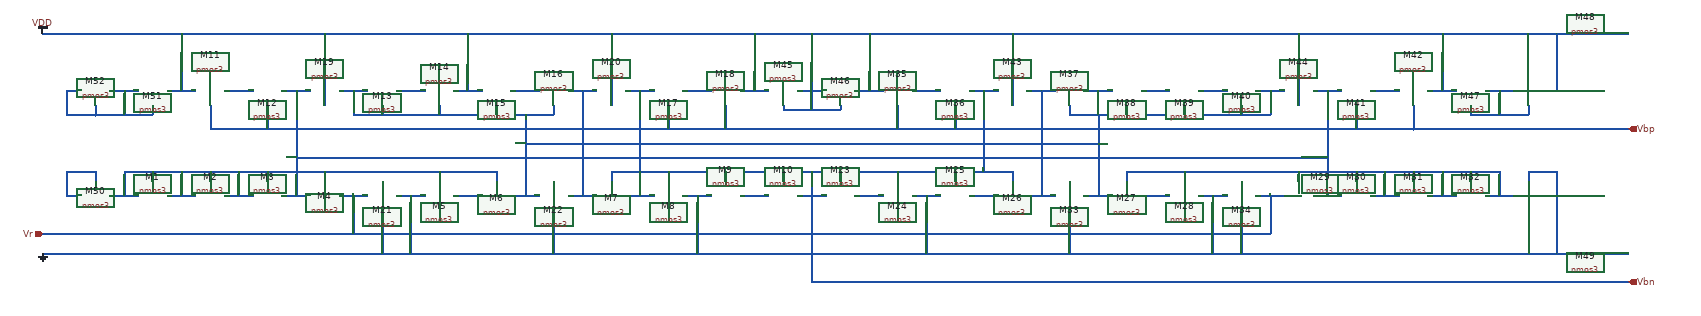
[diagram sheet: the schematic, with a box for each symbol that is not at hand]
v {xschem version=2.9.9 file_version=1.2 }
G {}
K {}
V {}
S {}
E {}
N 650 -270 650 -250 { lab=#net1}
N 530 -270 530 -250 { lab=#net1}
N 410 -270 410 -250 { lab=#net1}
N 290 -270 290 -250 { lab=#net1}
N 320 -220 380 -220 { lab=#net1}
N 350 -270 350 -220 { lab=#net1}
N 440 -220 500 -220 { lab=#net1}
N 470 -270 470 -220 { lab=#net1}
N 560 -220 620 -220 { lab=#net1}
N 590 -270 590 -220 { lab=#net1}
N 440 -440 500 -440 { lab=#net2}
N 800 -440 860 -440 { lab=#net3}
N 1040 -440 1100 -440 { lab=#net4}
N 1400 -440 1460 -440 { lab=#net5}
N 770 -410 770 -390 { lab=#net6}
N 1130 -410 1130 -390 { lab=#net6}
N 890 -410 890 -390 { lab=#net6}
N 1010 -410 1010 -390 { lab=#net6}
N 410 -410 410 -360 { lab=Vbp}
N 1490 -410 1490 -360 { lab=Vbp}
N 1370 -410 1370 -360 { lab=Vbp}
N 530 -410 530 -360 { lab=Vbp}
N 350 -560 350 -440 { lab=#net7}
N 1550 -560 1550 -440 { lab=#net7}
N 920 -440 980 -440 { lab=#net7}
N 950 -560 950 -440 { lab=#net7}
N 890 -270 890 -250 { lab=#net1}
N 1010 -270 1010 -250 { lab=#net1}
N 920 -220 980 -220 { lab=#net8}
N 1280 -220 1340 -220 { lab=#net9}
N 1520 -220 1580 -220 { lab=#net10}
N 710 -220 710 -140 { lab=Vr}
N 1250 -270 1250 -250 { lab=Vbn}
N 1610 -270 1610 -250 { lab=Vbn}
N 1490 -270 1490 -250 { lab=Vbn}
N 1370 -270 1370 -250 { lab=Vbn}
N 1400 -220 1460 -220 { lab=GND}
N 1430 -220 1430 -100 { lab=GND}
N 830 -220 830 -100 { lab=GND}
N 1670 -270 1670 -220 { lab=Vbn}
N 1190 -360 1190 -220 { lab=Vbp}
N 560 -440 620 -440 { lab=#net1}
N 680 -440 740 -440 { lab=#net6}
N 650 -560 650 -410 { lab=#net7}
N 590 -440 590 -270 { lab=#net1}
N 1280 -440 1340 -440 { lab=Vbn}
N 1310 -440 1310 -270 { lab=Vbn}
N 1160 -440 1220 -440 { lab=Vbp}
N 1190 -440 1190 -360 { lab=Vbp}
N 1250 -560 1250 -410 { lab=#net7}
N 800 -220 860 -220 { lab=GND}
N 680 -220 740 -220 { lab=Vr}
N 770 -250 770 -100 { lab=GND}
N 1040 -220 1100 -220 { lab=#net6}
N 1070 -390 1070 -220 { lab=#net6}
N 1160 -220 1220 -220 { lab=Vbp}
N 1130 -250 1130 -100 { lab=GND}
N 1730 -270 1730 -250 { lab=Vbn}
N 1850 -270 1850 -250 { lab=Vbn}
N 1970 -270 1970 -250 { lab=Vbn}
N 2090 -270 2090 -250 { lab=Vbn}
N 1640 -220 1700 -220 { lab=Vbn}
N 1250 -270 2090 -270 { lab=Vbn}
N 1760 -220 1820 -220 { lab=#net11}
N 1880 -220 1940 -220 { lab=GND}
N 2000 -220 2060 -220 { lab=#net12}
N 1910 -220 1910 -100 { lab=GND}
N 1520 -440 1580 -440 { lab=#net7}
N 1610 -410 1610 -400 { lab=#net7}
N 1610 -400 1730 -400 { lab=#net7}
N 1730 -410 1730 -400 { lab=#net7}
N 1640 -440 1700 -440 { lab=#net7}
N 1670 -560 1670 -440 { lab=#net7}
N 1670 -440 1670 -400 { lab=#net7}
N 1760 -440 1820 -440 { lab=#net7}
N 1790 -560 1790 -440 { lab=#net7}
N 1850 -410 1850 -360 { lab=Vbp}
N 1970 -410 1970 -360 { lab=Vbp}
N 2930 -410 2930 -360 { lab=Vbp}
N 2810 -410 2810 -360 { lab=Vbp}
N 2210 -410 2210 -390 { lab=#net6}
N 2330 -410 2330 -390 { lab=#net6}
N 2450 -410 2450 -390 { lab=#net6}
N 2570 -410 2570 -390 { lab=#net6}
N 2090 -560 2090 -410 { lab=#net7}
N 2690 -560 2690 -410 { lab=#net7}
N 710 -440 710 -390 { lab=#net6}
N 710 -390 1130 -390 { lab=#net6}
N 1880 -440 1940 -440 { lab=#net13}
N 2000 -440 2060 -440 { lab=Vbn}
N 2120 -440 2180 -440 { lab=Vbp}
N 2240 -440 2300 -440 { lab=#net14}
N 2360 -440 2420 -440 { lab=#net15}
N 2480 -440 2540 -440 { lab=#net16}
N 2600 -440 2660 -440 { lab=#net6}
N 2720 -440 2780 -440 { lab=#net1}
N 2840 -440 2900 -440 { lab=#net17}
N 2120 -220 2180 -220 { lab=Vbp}
N 2240 -220 2300 -220 { lab=#net6}
N 2360 -220 2420 -220 { lab=#net18}
N 2480 -220 2540 -220 { lab=GND}
N 2600 -220 2660 -220 { lab=Vr}
N 2720 -220 2780 -220 { lab=#net1}
N 2840 -220 2900 -220 { lab=#net1}
N 2960 -220 3020 -220 { lab=#net1}
N 3050 -270 3050 -250 { lab=#net1}
N 3110 -270 3110 -220 { lab=#net1}
N 2690 -270 2690 -250 { lab=#net1}
N 2810 -270 2810 -250 { lab=#net1}
N 2930 -270 2930 -250 { lab=#net1}
N 2750 -270 2750 -220 { lab=#net1}
N 2870 -270 2870 -220 { lab=#net1}
N 2990 -270 2990 -220 { lab=#net1}
N 410 -360 2930 -360 { lab=Vbp}
N 2630 -440 2630 -390 { lab=#net6}
N 2210 -390 2630 -390 { lab=#net6}
N 2030 -440 2030 -270 { lab=Vbn}
N 2150 -440 2150 -360 { lab=Vbp}
N 2150 -360 2150 -220 { lab=Vbp}
N 2210 -250 2210 -100 { lab=GND}
N 2570 -250 2570 -100 { lab=GND}
N 2510 -220 2510 -100 { lab=GND}
N 2630 -220 2630 -140 { lab=Vr}
N 2270 -390 2270 -220 { lab=#net6}
N 2330 -270 2330 -250 { lab=#net1}
N 2450 -270 2450 -250 { lab=#net1}
N 2330 -270 3110 -270 { lab=#net1}
N 2990 -560 2990 -440 { lab=#net7}
N 2750 -440 2750 -270 { lab=#net1}
N 1070 -330 2270 -330 { lab=#net6}
N 590 -300 2750 -300 { lab=#net1}
N 1670 -220 1670 -40 { lab=Vbn}
N 170 -270 170 -250 { lab=#net19}
N 110 -270 110 -220 { lab=#net19}
N 110 -220 140 -220 { lab=#net19}
N 110 -270 170 -270 { lab=#net19}
N 320 -440 380 -440 { lab=#net7}
N 290 -410 290 -390 { lab=#net20}
N 200 -220 260 -220 { lab=#net1}
N 230 -270 230 -220 { lab=#net1}
N 230 -270 1010 -270 { lab=#net1}
N 3080 -220 3140 -220 { lab=#net1}
N 3170 -270 3170 -250 { lab=GND}
N 3170 -270 3230 -270 { lab=GND}
N 3230 -270 3230 -220 { lab=GND}
N 3200 -220 3230 -220 { lab=GND}
N 3230 -220 3230 -100 { lab=GND}
N 2960 -440 3020 -440 { lab=#net7}
N 3050 -410 3050 -390 { lab=#net21}
N 3050 -390 3170 -390 { lab=#net21}
N 3170 -410 3170 -390 { lab=#net21}
N 3080 -440 3140 -440 { lab=#net21}
N 3110 -440 3110 -390 { lab=#net21}
N 3200 -440 3230 -440 { lab=#net7}
N 3230 -560 3230 -440 { lab=#net7}
N 200 -440 260 -440 { lab=#net20}
N 170 -410 170 -390 { lab=#net20}
N 170 -390 290 -390 { lab=#net20}
N 230 -440 230 -390 { lab=#net20}
N 110 -390 170 -390 { lab=#net20}
N 110 -440 110 -390 { lab=#net20}
N 110 -440 140 -440 { lab=#net20}
N 60 -140 2630 -140 { lab=Vr}
N 60 -100 3380 -100 { lab=GND}
N 1670 -40 3380 -40 { lab=Vbn}
N 2930 -360 3380 -360 {}
N 60 -560 3380 -560 { lab=GND}
C {devices/iopin.sym} 60 -140 2 0 {name=p4 lab=Vr}
C {madvlsi/nmos3.sym} 290 -220 1 0 {name=M1
L=4.0
W=16
body=GND
nf=1
mult=1
ad="'int((nf+1)/2) * W/nf * 0.29'" 
pd="'2*int((nf+1)/2) * (W/nf + 0.29)'"
as="'int((nf+2)/2) * W/nf * 0.29'" 
ps="'2*int((nf+2)/2) * (W/nf + 0.29)'"
nrd="'0.29 / W'" nrs="'0.29 / W'"
sa=0 sb=0 sd=0
model=nfet_01v8
spiceprefix=X
}
C {madvlsi/nmos3.sym} 410 -220 1 0 {name=M2
L=4.0
W=16
body=GND
nf=1
mult=1
ad="'int((nf+1)/2) * W/nf * 0.29'" 
pd="'2*int((nf+1)/2) * (W/nf + 0.29)'"
as="'int((nf+2)/2) * W/nf * 0.29'" 
ps="'2*int((nf+2)/2) * (W/nf + 0.29)'"
nrd="'0.29 / W'" nrs="'0.29 / W'"
sa=0 sb=0 sd=0
model=nfet_01v8
spiceprefix=X
}
C {madvlsi/nmos3.sym} 530 -220 1 0 {name=M3
L=4.0
W=16
body=GND
nf=1
mult=1
ad="'int((nf+1)/2) * W/nf * 0.29'" 
pd="'2*int((nf+1)/2) * (W/nf + 0.29)'"
as="'int((nf+2)/2) * W/nf * 0.29'" 
ps="'2*int((nf+2)/2) * (W/nf + 0.29)'"
nrd="'0.29 / W'" nrs="'0.29 / W'"
sa=0 sb=0 sd=0
model=nfet_01v8
spiceprefix=X
}
C {madvlsi/nmos3.sym} 650 -220 1 0 {name=M4
L=4.0
W=16
body=GND
nf=1
mult=1
ad="'int((nf+1)/2) * W/nf * 0.29'" 
pd="'2*int((nf+1)/2) * (W/nf + 0.29)'"
as="'int((nf+2)/2) * W/nf * 0.29'" 
ps="'2*int((nf+2)/2) * (W/nf + 0.29)'"
nrd="'0.29 / W'" nrs="'0.29 / W'"
sa=0 sb=0 sd=0
model=nfet_01v8
spiceprefix=X
}
C {madvlsi/nmos3.sym} 890 -220 1 0 {name=M5
L=4.0
W=16
body=GND
nf=1
mult=1
ad="'int((nf+1)/2) * W/nf * 0.29'" 
pd="'2*int((nf+1)/2) * (W/nf + 0.29)'"
as="'int((nf+2)/2) * W/nf * 0.29'" 
ps="'2*int((nf+2)/2) * (W/nf + 0.29)'"
nrd="'0.29 / W'" nrs="'0.29 / W'"
sa=0 sb=0 sd=0
model=nfet_01v8
spiceprefix=X
}
C {madvlsi/nmos3.sym} 1010 -220 1 0 {name=M6
L=4.0
W=16
body=GND
nf=1
mult=1
ad="'int((nf+1)/2) * W/nf * 0.29'" 
pd="'2*int((nf+1)/2) * (W/nf + 0.29)'"
as="'int((nf+2)/2) * W/nf * 0.29'" 
ps="'2*int((nf+2)/2) * (W/nf + 0.29)'"
nrd="'0.29 / W'" nrs="'0.29 / W'"
sa=0 sb=0 sd=0
model=nfet_01v8
spiceprefix=X
}
C {madvlsi/nmos3.sym} 1250 -220 1 0 {name=M7
L=4.0
W=16
body=GND
nf=1
mult=1
ad="'int((nf+1)/2) * W/nf * 0.29'" 
pd="'2*int((nf+1)/2) * (W/nf + 0.29)'"
as="'int((nf+2)/2) * W/nf * 0.29'" 
ps="'2*int((nf+2)/2) * (W/nf + 0.29)'"
nrd="'0.29 / W'" nrs="'0.29 / W'"
sa=0 sb=0 sd=0
model=nfet_01v8
spiceprefix=X
}
C {madvlsi/nmos3.sym} 1370 -220 1 0 {name=M8
L=4.0
W=16
body=GND
nf=1
mult=1
ad="'int((nf+1)/2) * W/nf * 0.29'" 
pd="'2*int((nf+1)/2) * (W/nf + 0.29)'"
as="'int((nf+2)/2) * W/nf * 0.29'" 
ps="'2*int((nf+2)/2) * (W/nf + 0.29)'"
nrd="'0.29 / W'" nrs="'0.29 / W'"
sa=0 sb=0 sd=0
model=nfet_01v8
spiceprefix=X
}
C {madvlsi/nmos3.sym} 1490 -220 1 0 {name=M9
L=4.0
W=16
body=GND
nf=1
mult=1
ad="'int((nf+1)/2) * W/nf * 0.29'" 
pd="'2*int((nf+1)/2) * (W/nf + 0.29)'"
as="'int((nf+2)/2) * W/nf * 0.29'" 
ps="'2*int((nf+2)/2) * (W/nf + 0.29)'"
nrd="'0.29 / W'" nrs="'0.29 / W'"
sa=0 sb=0 sd=0
model=nfet_01v8
spiceprefix=X
}
C {madvlsi/nmos3.sym} 1610 -220 1 0 {name=M10
L=4.0
W=16
body=GND
nf=1
mult=1
ad="'int((nf+1)/2) * W/nf * 0.29'" 
pd="'2*int((nf+1)/2) * (W/nf + 0.29)'"
as="'int((nf+2)/2) * W/nf * 0.29'" 
ps="'2*int((nf+2)/2) * (W/nf + 0.29)'"
nrd="'0.29 / W'" nrs="'0.29 / W'"
sa=0 sb=0 sd=0
model=nfet_01v8
spiceprefix=X
}
C {madvlsi/pmos3.sym} 410 -440 1 1 {name=M11
L=4.0
W=16
body=VDD
nf=1
mult=1
ad="'int((nf+1)/2) * W/nf * 0.29'" 
pd="'2*int((nf+1)/2) * (W/nf + 0.29)'"
as="'int((nf+2)/2) * W/nf * 0.29'" 
ps="'2*int((nf+2)/2) * (W/nf + 0.29)'"
nrd="'0.29 / W'" nrs="'0.29 / W'"
sa=0 sb=0 sd=0
model=pfet_01v8
spiceprefix=X
}
C {madvlsi/pmos3.sym} 530 -440 1 1 {name=M12
L=4.0
W=16
body=VDD
nf=1
mult=1
ad="'int((nf+1)/2) * W/nf * 0.29'" 
pd="'2*int((nf+1)/2) * (W/nf + 0.29)'"
as="'int((nf+2)/2) * W/nf * 0.29'" 
ps="'2*int((nf+2)/2) * (W/nf + 0.29)'"
nrd="'0.29 / W'" nrs="'0.29 / W'"
sa=0 sb=0 sd=0
model=pfet_01v8
spiceprefix=X
}
C {madvlsi/pmos3.sym} 770 -440 1 1 {name=M13
L=4.0
W=16
body=VDD
nf=1
mult=1
ad="'int((nf+1)/2) * W/nf * 0.29'" 
pd="'2*int((nf+1)/2) * (W/nf + 0.29)'"
as="'int((nf+2)/2) * W/nf * 0.29'" 
ps="'2*int((nf+2)/2) * (W/nf + 0.29)'"
nrd="'0.29 / W'" nrs="'0.29 / W'"
sa=0 sb=0 sd=0
model=pfet_01v8
spiceprefix=X
}
C {madvlsi/pmos3.sym} 890 -440 1 1 {name=M14
L=4.0
W=16
body=VDD
nf=1
mult=1
ad="'int((nf+1)/2) * W/nf * 0.29'" 
pd="'2*int((nf+1)/2) * (W/nf + 0.29)'"
as="'int((nf+2)/2) * W/nf * 0.29'" 
ps="'2*int((nf+2)/2) * (W/nf + 0.29)'"
nrd="'0.29 / W'" nrs="'0.29 / W'"
sa=0 sb=0 sd=0
model=pfet_01v8
spiceprefix=X
}
C {madvlsi/pmos3.sym} 1010 -440 1 1 {name=M15
L=4.0
W=16
body=VDD
nf=1
mult=1
ad="'int((nf+1)/2) * W/nf * 0.29'" 
pd="'2*int((nf+1)/2) * (W/nf + 0.29)'"
as="'int((nf+2)/2) * W/nf * 0.29'" 
ps="'2*int((nf+2)/2) * (W/nf + 0.29)'"
nrd="'0.29 / W'" nrs="'0.29 / W'"
sa=0 sb=0 sd=0
model=pfet_01v8
spiceprefix=X
}
C {madvlsi/pmos3.sym} 1130 -440 1 1 {name=M16
L=4.0
W=16
body=VDD
nf=1
mult=1
ad="'int((nf+1)/2) * W/nf * 0.29'" 
pd="'2*int((nf+1)/2) * (W/nf + 0.29)'"
as="'int((nf+2)/2) * W/nf * 0.29'" 
ps="'2*int((nf+2)/2) * (W/nf + 0.29)'"
nrd="'0.29 / W'" nrs="'0.29 / W'"
sa=0 sb=0 sd=0
model=pfet_01v8
spiceprefix=X
}
C {madvlsi/pmos3.sym} 1370 -440 1 1 {name=M17
L=4.0
W=16
body=VDD
nf=1
mult=1
ad="'int((nf+1)/2) * W/nf * 0.29'" 
pd="'2*int((nf+1)/2) * (W/nf + 0.29)'"
as="'int((nf+2)/2) * W/nf * 0.29'" 
ps="'2*int((nf+2)/2) * (W/nf + 0.29)'"
nrd="'0.29 / W'" nrs="'0.29 / W'"
sa=0 sb=0 sd=0
model=pfet_01v8
spiceprefix=X
}
C {madvlsi/pmos3.sym} 1490 -440 1 1 {name=M18
L=4.0
W=16
body=VDD
nf=1
mult=1
ad="'int((nf+1)/2) * W/nf * 0.29'" 
pd="'2*int((nf+1)/2) * (W/nf + 0.29)'"
as="'int((nf+2)/2) * W/nf * 0.29'" 
ps="'2*int((nf+2)/2) * (W/nf + 0.29)'"
nrd="'0.29 / W'" nrs="'0.29 / W'"
sa=0 sb=0 sd=0
model=pfet_01v8
spiceprefix=X
}
C {madvlsi/pmos3.sym} 650 -440 1 1 {name=M19
L=4.0
W=16
body=VDD
nf=1
mult=1
ad="'int((nf+1)/2) * W/nf * 0.29'" 
pd="'2*int((nf+1)/2) * (W/nf + 0.29)'"
as="'int((nf+2)/2) * W/nf * 0.29'" 
ps="'2*int((nf+2)/2) * (W/nf + 0.29)'"
nrd="'0.29 / W'" nrs="'0.29 / W'"
sa=0 sb=0 sd=0
model=pfet_01v8
spiceprefix=X
}
C {madvlsi/pmos3.sym} 1250 -440 1 1 {name=M20
L=4.0
W=16
body=VDD
nf=1
mult=1
ad="'int((nf+1)/2) * W/nf * 0.29'" 
pd="'2*int((nf+1)/2) * (W/nf + 0.29)'"
as="'int((nf+2)/2) * W/nf * 0.29'" 
ps="'2*int((nf+2)/2) * (W/nf + 0.29)'"
nrd="'0.29 / W'" nrs="'0.29 / W'"
sa=0 sb=0 sd=0
model=pfet_01v8
spiceprefix=X
}
C {madvlsi/nmos3.sym} 770 -220 1 0 {name=M21
L=4.0
W=16
body=GND
nf=1
mult=1
ad="'int((nf+1)/2) * W/nf * 0.29'" 
pd="'2*int((nf+1)/2) * (W/nf + 0.29)'"
as="'int((nf+2)/2) * W/nf * 0.29'" 
ps="'2*int((nf+2)/2) * (W/nf + 0.29)'"
nrd="'0.29 / W'" nrs="'0.29 / W'"
sa=0 sb=0 sd=0
model=nfet_01v8
spiceprefix=X
}
C {madvlsi/nmos3.sym} 1130 -220 1 0 {name=M22
L=4.0
W=16
body=GND
nf=1
mult=1
ad="'int((nf+1)/2) * W/nf * 0.29'" 
pd="'2*int((nf+1)/2) * (W/nf + 0.29)'"
as="'int((nf+2)/2) * W/nf * 0.29'" 
ps="'2*int((nf+2)/2) * (W/nf + 0.29)'"
nrd="'0.29 / W'" nrs="'0.29 / W'"
sa=0 sb=0 sd=0
model=nfet_01v8
spiceprefix=X
}
C {madvlsi/nmos3.sym} 1730 -220 1 0 {name=M23
L=4.0
W=16
body=GND
nf=1
mult=1
ad="'int((nf+1)/2) * W/nf * 0.29'" 
pd="'2*int((nf+1)/2) * (W/nf + 0.29)'"
as="'int((nf+2)/2) * W/nf * 0.29'" 
ps="'2*int((nf+2)/2) * (W/nf + 0.29)'"
nrd="'0.29 / W'" nrs="'0.29 / W'"
sa=0 sb=0 sd=0
model=nfet_01v8
spiceprefix=X
}
C {madvlsi/nmos3.sym} 1850 -220 1 0 {name=M24
L=4.0
W=16
body=GND
nf=1
mult=1
ad="'int((nf+1)/2) * W/nf * 0.29'" 
pd="'2*int((nf+1)/2) * (W/nf + 0.29)'"
as="'int((nf+2)/2) * W/nf * 0.29'" 
ps="'2*int((nf+2)/2) * (W/nf + 0.29)'"
nrd="'0.29 / W'" nrs="'0.29 / W'"
sa=0 sb=0 sd=0
model=nfet_01v8
spiceprefix=X
}
C {madvlsi/nmos3.sym} 1970 -220 1 0 {name=M25
L=4.0
W=16
body=GND
nf=1
mult=1
ad="'int((nf+1)/2) * W/nf * 0.29'" 
pd="'2*int((nf+1)/2) * (W/nf + 0.29)'"
as="'int((nf+2)/2) * W/nf * 0.29'" 
ps="'2*int((nf+2)/2) * (W/nf + 0.29)'"
nrd="'0.29 / W'" nrs="'0.29 / W'"
sa=0 sb=0 sd=0
model=nfet_01v8
spiceprefix=X
}
C {madvlsi/nmos3.sym} 2090 -220 1 0 {name=M26
L=4.0
W=16
body=GND
nf=1
mult=1
ad="'int((nf+1)/2) * W/nf * 0.29'" 
pd="'2*int((nf+1)/2) * (W/nf + 0.29)'"
as="'int((nf+2)/2) * W/nf * 0.29'" 
ps="'2*int((nf+2)/2) * (W/nf + 0.29)'"
nrd="'0.29 / W'" nrs="'0.29 / W'"
sa=0 sb=0 sd=0
model=nfet_01v8
spiceprefix=X
}
C {madvlsi/nmos3.sym} 2330 -220 1 0 {name=M27
L=4.0
W=16
body=GND
nf=1
mult=1
ad="'int((nf+1)/2) * W/nf * 0.29'" 
pd="'2*int((nf+1)/2) * (W/nf + 0.29)'"
as="'int((nf+2)/2) * W/nf * 0.29'" 
ps="'2*int((nf+2)/2) * (W/nf + 0.29)'"
nrd="'0.29 / W'" nrs="'0.29 / W'"
sa=0 sb=0 sd=0
model=nfet_01v8
spiceprefix=X
}
C {madvlsi/nmos3.sym} 2450 -220 1 0 {name=M28
L=4.0
W=16
body=GND
nf=1
mult=1
ad="'int((nf+1)/2) * W/nf * 0.29'" 
pd="'2*int((nf+1)/2) * (W/nf + 0.29)'"
as="'int((nf+2)/2) * W/nf * 0.29'" 
ps="'2*int((nf+2)/2) * (W/nf + 0.29)'"
nrd="'0.29 / W'" nrs="'0.29 / W'"
sa=0 sb=0 sd=0
model=nfet_01v8
spiceprefix=X
}
C {madvlsi/nmos3.sym} 2690 -220 1 0 {name=M29
L=4.0
W=16
body=GND
nf=1
mult=1
ad="'int((nf+1)/2) * W/nf * 0.29'" 
pd="'2*int((nf+1)/2) * (W/nf + 0.29)'"
as="'int((nf+2)/2) * W/nf * 0.29'" 
ps="'2*int((nf+2)/2) * (W/nf + 0.29)'"
nrd="'0.29 / W'" nrs="'0.29 / W'"
sa=0 sb=0 sd=0
model=nfet_01v8
spiceprefix=X
}
C {madvlsi/nmos3.sym} 2810 -220 1 0 {name=M30
L=4.0
W=16
body=GND
nf=1
mult=1
ad="'int((nf+1)/2) * W/nf * 0.29'" 
pd="'2*int((nf+1)/2) * (W/nf + 0.29)'"
as="'int((nf+2)/2) * W/nf * 0.29'" 
ps="'2*int((nf+2)/2) * (W/nf + 0.29)'"
nrd="'0.29 / W'" nrs="'0.29 / W'"
sa=0 sb=0 sd=0
model=nfet_01v8
spiceprefix=X
}
C {madvlsi/nmos3.sym} 2930 -220 1 0 {name=M31
L=4.0
W=16
body=GND
nf=1
mult=1
ad="'int((nf+1)/2) * W/nf * 0.29'" 
pd="'2*int((nf+1)/2) * (W/nf + 0.29)'"
as="'int((nf+2)/2) * W/nf * 0.29'" 
ps="'2*int((nf+2)/2) * (W/nf + 0.29)'"
nrd="'0.29 / W'" nrs="'0.29 / W'"
sa=0 sb=0 sd=0
model=nfet_01v8
spiceprefix=X
}
C {madvlsi/nmos3.sym} 3050 -220 1 0 {name=M32
L=4.0
W=16
body=GND
nf=1
mult=1
ad="'int((nf+1)/2) * W/nf * 0.29'" 
pd="'2*int((nf+1)/2) * (W/nf + 0.29)'"
as="'int((nf+2)/2) * W/nf * 0.29'" 
ps="'2*int((nf+2)/2) * (W/nf + 0.29)'"
nrd="'0.29 / W'" nrs="'0.29 / W'"
sa=0 sb=0 sd=0
model=nfet_01v8
spiceprefix=X
}
C {madvlsi/nmos3.sym} 2210 -220 1 0 {name=M33
L=4.0
W=16
body=GND
nf=1
mult=1
ad="'int((nf+1)/2) * W/nf * 0.29'" 
pd="'2*int((nf+1)/2) * (W/nf + 0.29)'"
as="'int((nf+2)/2) * W/nf * 0.29'" 
ps="'2*int((nf+2)/2) * (W/nf + 0.29)'"
nrd="'0.29 / W'" nrs="'0.29 / W'"
sa=0 sb=0 sd=0
model=nfet_01v8
spiceprefix=X
}
C {madvlsi/nmos3.sym} 2570 -220 1 0 {name=M34
L=4.0
W=16
body=GND
nf=1
mult=1
ad="'int((nf+1)/2) * W/nf * 0.29'" 
pd="'2*int((nf+1)/2) * (W/nf + 0.29)'"
as="'int((nf+2)/2) * W/nf * 0.29'" 
ps="'2*int((nf+2)/2) * (W/nf + 0.29)'"
nrd="'0.29 / W'" nrs="'0.29 / W'"
sa=0 sb=0 sd=0
model=nfet_01v8
spiceprefix=X
}
C {madvlsi/pmos3.sym} 1850 -440 1 1 {name=M35
L=4.0
W=16
body=VDD
nf=1
mult=1
ad="'int((nf+1)/2) * W/nf * 0.29'" 
pd="'2*int((nf+1)/2) * (W/nf + 0.29)'"
as="'int((nf+2)/2) * W/nf * 0.29'" 
ps="'2*int((nf+2)/2) * (W/nf + 0.29)'"
nrd="'0.29 / W'" nrs="'0.29 / W'"
sa=0 sb=0 sd=0
model=pfet_01v8
spiceprefix=X
}
C {madvlsi/pmos3.sym} 1970 -440 1 1 {name=M36
L=4.0
W=16
body=VDD
nf=1
mult=1
ad="'int((nf+1)/2) * W/nf * 0.29'" 
pd="'2*int((nf+1)/2) * (W/nf + 0.29)'"
as="'int((nf+2)/2) * W/nf * 0.29'" 
ps="'2*int((nf+2)/2) * (W/nf + 0.29)'"
nrd="'0.29 / W'" nrs="'0.29 / W'"
sa=0 sb=0 sd=0
model=pfet_01v8
spiceprefix=X
}
C {madvlsi/pmos3.sym} 2210 -440 1 1 {name=M37
L=4.0
W=16
body=VDD
nf=1
mult=1
ad="'int((nf+1)/2) * W/nf * 0.29'" 
pd="'2*int((nf+1)/2) * (W/nf + 0.29)'"
as="'int((nf+2)/2) * W/nf * 0.29'" 
ps="'2*int((nf+2)/2) * (W/nf + 0.29)'"
nrd="'0.29 / W'" nrs="'0.29 / W'"
sa=0 sb=0 sd=0
model=pfet_01v8
spiceprefix=X
}
C {madvlsi/pmos3.sym} 2330 -440 1 1 {name=M38
L=4.0
W=16
body=VDD
nf=1
mult=1
ad="'int((nf+1)/2) * W/nf * 0.29'" 
pd="'2*int((nf+1)/2) * (W/nf + 0.29)'"
as="'int((nf+2)/2) * W/nf * 0.29'" 
ps="'2*int((nf+2)/2) * (W/nf + 0.29)'"
nrd="'0.29 / W'" nrs="'0.29 / W'"
sa=0 sb=0 sd=0
model=pfet_01v8
spiceprefix=X
}
C {madvlsi/pmos3.sym} 2450 -440 1 1 {name=M39
L=4.0
W=16
body=VDD
nf=1
mult=1
ad="'int((nf+1)/2) * W/nf * 0.29'" 
pd="'2*int((nf+1)/2) * (W/nf + 0.29)'"
as="'int((nf+2)/2) * W/nf * 0.29'" 
ps="'2*int((nf+2)/2) * (W/nf + 0.29)'"
nrd="'0.29 / W'" nrs="'0.29 / W'"
sa=0 sb=0 sd=0
model=pfet_01v8
spiceprefix=X
}
C {madvlsi/pmos3.sym} 2570 -440 1 1 {name=M40
L=4.0
W=16
body=VDD
nf=1
mult=1
ad="'int((nf+1)/2) * W/nf * 0.29'" 
pd="'2*int((nf+1)/2) * (W/nf + 0.29)'"
as="'int((nf+2)/2) * W/nf * 0.29'" 
ps="'2*int((nf+2)/2) * (W/nf + 0.29)'"
nrd="'0.29 / W'" nrs="'0.29 / W'"
sa=0 sb=0 sd=0
model=pfet_01v8
spiceprefix=X
}
C {madvlsi/pmos3.sym} 2810 -440 1 1 {name=M41
L=4.0
W=16
body=VDD
nf=1
mult=1
ad="'int((nf+1)/2) * W/nf * 0.29'" 
pd="'2*int((nf+1)/2) * (W/nf + 0.29)'"
as="'int((nf+2)/2) * W/nf * 0.29'" 
ps="'2*int((nf+2)/2) * (W/nf + 0.29)'"
nrd="'0.29 / W'" nrs="'0.29 / W'"
sa=0 sb=0 sd=0
model=pfet_01v8
spiceprefix=X
}
C {madvlsi/pmos3.sym} 2930 -440 1 1 {name=M42
L=4.0
W=16
body=VDD
nf=1
mult=1
ad="'int((nf+1)/2) * W/nf * 0.29'" 
pd="'2*int((nf+1)/2) * (W/nf + 0.29)'"
as="'int((nf+2)/2) * W/nf * 0.29'" 
ps="'2*int((nf+2)/2) * (W/nf + 0.29)'"
nrd="'0.29 / W'" nrs="'0.29 / W'"
sa=0 sb=0 sd=0
model=pfet_01v8
spiceprefix=X
}
C {madvlsi/pmos3.sym} 2090 -440 1 1 {name=M43
L=4.0
W=16
body=VDD
nf=1
mult=1
ad="'int((nf+1)/2) * W/nf * 0.29'" 
pd="'2*int((nf+1)/2) * (W/nf + 0.29)'"
as="'int((nf+2)/2) * W/nf * 0.29'" 
ps="'2*int((nf+2)/2) * (W/nf + 0.29)'"
nrd="'0.29 / W'" nrs="'0.29 / W'"
sa=0 sb=0 sd=0
model=pfet_01v8
spiceprefix=X
}
C {madvlsi/pmos3.sym} 2690 -440 1 1 {name=M44
L=4.0
W=16
body=VDD
nf=1
mult=1
ad="'int((nf+1)/2) * W/nf * 0.29'" 
pd="'2*int((nf+1)/2) * (W/nf + 0.29)'"
as="'int((nf+2)/2) * W/nf * 0.29'" 
ps="'2*int((nf+2)/2) * (W/nf + 0.29)'"
nrd="'0.29 / W'" nrs="'0.29 / W'"
sa=0 sb=0 sd=0
model=pfet_01v8
spiceprefix=X
}
C {madvlsi/pmos3.sym} 1610 -440 1 1 {name=M45
L=4.0
W=16
body=VDD
nf=1
mult=1
ad="'int((nf+1)/2) * W/nf * 0.29'" 
pd="'2*int((nf+1)/2) * (W/nf + 0.29)'"
as="'int((nf+2)/2) * W/nf * 0.29'" 
ps="'2*int((nf+2)/2) * (W/nf + 0.29)'"
nrd="'0.29 / W'" nrs="'0.29 / W'"
sa=0 sb=0 sd=0
model=pfet_01v8
spiceprefix=X
}
C {madvlsi/pmos3.sym} 1730 -440 1 1 {name=M46
L=4.0
W=16
body=VDD
nf=1
mult=1
ad="'int((nf+1)/2) * W/nf * 0.29'" 
pd="'2*int((nf+1)/2) * (W/nf + 0.29)'"
as="'int((nf+2)/2) * W/nf * 0.29'" 
ps="'2*int((nf+2)/2) * (W/nf + 0.29)'"
nrd="'0.29 / W'" nrs="'0.29 / W'"
sa=0 sb=0 sd=0
model=pfet_01v8
spiceprefix=X
}
C {devices/opin.sym} 3380 -360 0 0 {name=p5 lab=Vbp}
C {devices/opin.sym} 3380 -40 0 0 {name=p6 lab=Vbn}
C {madvlsi/gnd.sym} 60 -100 1 0 {name=l5 lab=GND}
C {madvlsi/vdd.sym} 60 -560 3 0 {name=l9 lab=VDD}
C {madvlsi/pmos3.sym} 3050 -440 1 1 {name=M47
L=4.0
W=16
body=VDD
nf=1
mult=1
ad="'int((nf+1)/2) * W/nf * 0.29'" 
pd="'2*int((nf+1)/2) * (W/nf + 0.29)'"
as="'int((nf+2)/2) * W/nf * 0.29'" 
ps="'2*int((nf+2)/2) * (W/nf + 0.29)'"
nrd="'0.29 / W'" nrs="'0.29 / W'"
sa=0 sb=0 sd=0
model=pfet_01v8
spiceprefix=X
}
C {madvlsi/pmos3.sym} 3170 -440 1 1 {name=M48
L=4.0
W=16
body=VDD
nf=1
mult=1
ad="'int((nf+1)/2) * W/nf * 0.29'" 
pd="'2*int((nf+1)/2) * (W/nf + 0.29)'"
as="'int((nf+2)/2) * W/nf * 0.29'" 
ps="'2*int((nf+2)/2) * (W/nf + 0.29)'"
nrd="'0.29 / W'" nrs="'0.29 / W'"
sa=0 sb=0 sd=0
model=pfet_01v8
spiceprefix=X
}
C {madvlsi/nmos3.sym} 3170 -220 1 0 {name=M49
L=4.0
W=16
body=GND
nf=1
mult=1
ad="'int((nf+1)/2) * W/nf * 0.29'" 
pd="'2*int((nf+1)/2) * (W/nf + 0.29)'"
as="'int((nf+2)/2) * W/nf * 0.29'" 
ps="'2*int((nf+2)/2) * (W/nf + 0.29)'"
nrd="'0.29 / W'" nrs="'0.29 / W'"
sa=0 sb=0 sd=0
model=nfet_01v8
spiceprefix=X
}
C {madvlsi/nmos3.sym} 170 -220 1 0 {name=M50
L=4.0
W=16
body=GND
nf=1
mult=1
ad="'int((nf+1)/2) * W/nf * 0.29'" 
pd="'2*int((nf+1)/2) * (W/nf + 0.29)'"
as="'int((nf+2)/2) * W/nf * 0.29'" 
ps="'2*int((nf+2)/2) * (W/nf + 0.29)'"
nrd="'0.29 / W'" nrs="'0.29 / W'"
sa=0 sb=0 sd=0
model=nfet_01v8
spiceprefix=X
}
C {madvlsi/pmos3.sym} 290 -440 1 1 {name=M51
L=4.0
W=16
body=VDD
nf=1
mult=1
ad="'int((nf+1)/2) * W/nf * 0.29'" 
pd="'2*int((nf+1)/2) * (W/nf + 0.29)'"
as="'int((nf+2)/2) * W/nf * 0.29'" 
ps="'2*int((nf+2)/2) * (W/nf + 0.29)'"
nrd="'0.29 / W'" nrs="'0.29 / W'"
sa=0 sb=0 sd=0
model=pfet_01v8
spiceprefix=X
}
C {madvlsi/pmos3.sym} 170 -440 1 1 {name=M52
L=4.0
W=16
body=VDD
nf=1
mult=1
ad="'int((nf+1)/2) * W/nf * 0.29'" 
pd="'2*int((nf+1)/2) * (W/nf + 0.29)'"
as="'int((nf+2)/2) * W/nf * 0.29'" 
ps="'2*int((nf+2)/2) * (W/nf + 0.29)'"
nrd="'0.29 / W'" nrs="'0.29 / W'"
sa=0 sb=0 sd=0
model=pfet_01v8
spiceprefix=X
}
